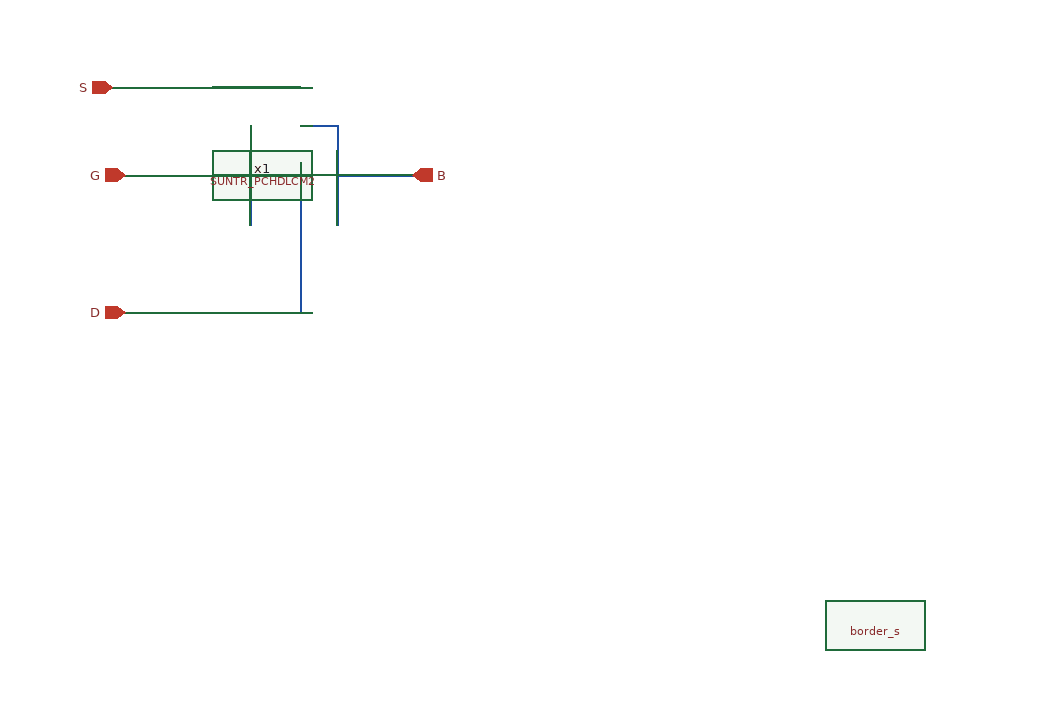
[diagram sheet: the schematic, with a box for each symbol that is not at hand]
v {xschem version=3.0.0 file_version=1.2 }
G {}
K {}
V {}
S {}
E {}
N 110 -730 110 -710 {
lab=#net1}
N 140 -760 140 -680 {
lab=B}
N 110 -760 140 -760 {
lab=B}
N 70 -760 70 -680 {
lab=G}
N 110 -650 110 -610 {
lab=D}
N 140 -720 210 -720 {
lab=B}
N -50 -790 110 -790 {
lab=S}
N -40 -610 110 -610 {
lab=D}
N -40 -720 70 -720 {
lab=G}
N 110 -710 110 -650 {}
C {SUN_TR_SKY130NM/SUNTR_PCHDLCM2.sym} 70 -760 0 0 {name=x1}
C {devices/iopin.sym} -30 -720 2 0 {name=p1 lab=G}
C {devices/iopin.sym} -30 -610 2 0 {name=p2 lab=D}
C {devices/iopin.sym} -40 -790 2 0 {name=p3 lab=S}
C {devices/iopin.sym} 200 -720 2 1 {name=p4 lab=B}
C {cborder/border_s.sym} 570 -360 0 0 {}
